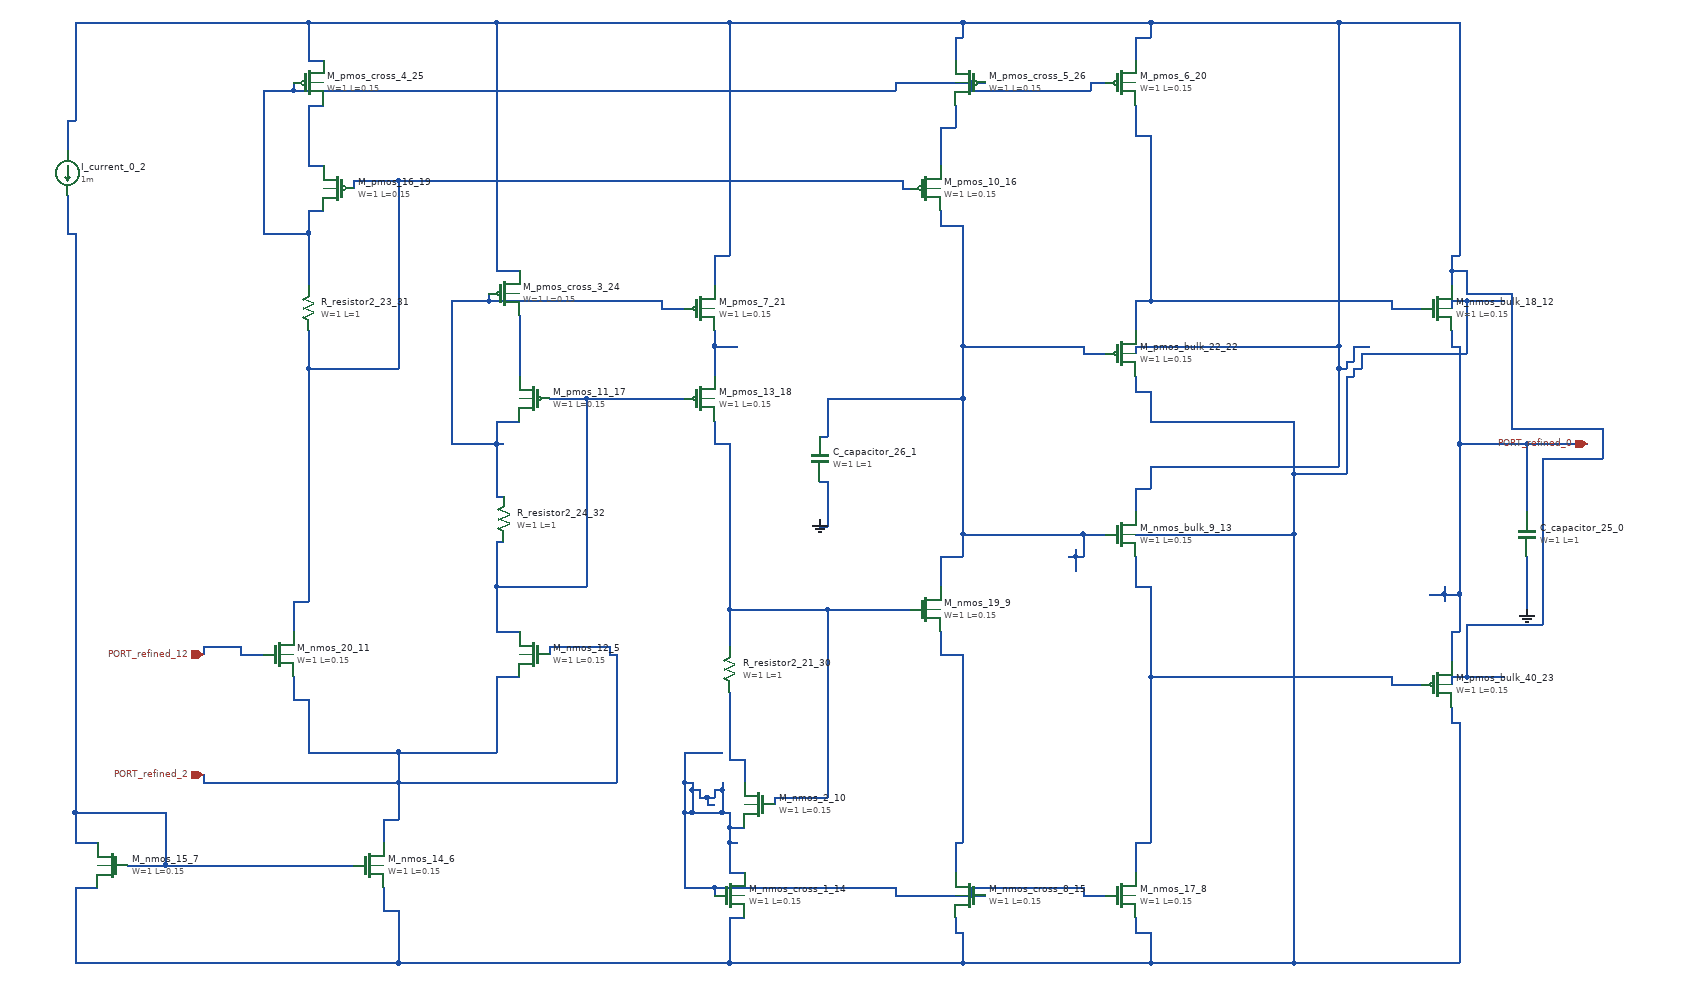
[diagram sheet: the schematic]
v {xschem version=3.4.8 file_version=1.2}
G {}
K {}
V {}
S {}
E {}
C {sky130_fd_pr/cap_mim_m3_1.sym} 2040 780 2 0 {name="C_capacitor_25_0" model=cap_mim_m3_1 W=1 L=1 MF=1 spiceprefix=X}
C {sky130_fd_pr/cap_mim_m3_1.sym} 1100 680 2 0 {name="C_capacitor_26_1" model=cap_mim_m3_1 W=1 L=1 MF=1 spiceprefix=X}
C {devices/isource.sym} 100 300 0 0 {name="I_current_0_2" value=1m}
C {devices/gnd.sym} 1100 760 0 0 {name="l_gnd_27_3" lab="GND"}
C {devices/gnd.sym} 2040 880 0 0 {name="l_gnd_28_4" lab="GND"}
C {sky130_fd_pr/nfet3_01v8.sym} 720 940 0 1 {name="M_nmos_12_5"
W=1
L=0.15
body=GND
nf=1
mult=1
ad="expr('int((@nf + 1)/2) * @W / @nf * 0.29')"
pd="expr('2*int((@nf + 1)/2) * (@W / @nf + 0.29)')"
as="expr('int((@nf + 2)/2) * @W / @nf * 0.29')"
ps="expr('2*int((@nf + 2)/2) * (@W / @nf + 0.29)')"
nrd="expr('0.29 / @W ')" nrs="expr('0.29 / @W ')"
sa=0 sb=0 sd=0
model=nfet_01v8
spiceprefix=X
}
C {sky130_fd_pr/nfet3_01v8.sym} 500 1220 0 0 {name="M_nmos_14_6"
W=1
L=0.15
body=GND
nf=1
mult=1
ad="expr('int((@nf + 1)/2) * @W / @nf * 0.29')"
pd="expr('2*int((@nf + 1)/2) * (@W / @nf + 0.29)')"
as="expr('int((@nf + 2)/2) * @W / @nf * 0.29')"
ps="expr('2*int((@nf + 2)/2) * (@W / @nf + 0.29)')"
nrd="expr('0.29 / @W ')" nrs="expr('0.29 / @W ')"
sa=0 sb=0 sd=0
model=nfet_01v8
spiceprefix=X
}
C {sky130_fd_pr/nfet3_01v8.sym} 160 1220 0 1 {name="M_nmos_15_7"
W=1
L=0.15
body=GND
nf=1
mult=1
ad="expr('int((@nf + 1)/2) * @W / @nf * 0.29')"
pd="expr('2*int((@nf + 1)/2) * (@W / @nf + 0.29)')"
as="expr('int((@nf + 2)/2) * @W / @nf * 0.29')"
ps="expr('2*int((@nf + 2)/2) * (@W / @nf + 0.29)')"
nrd="expr('0.29 / @W ')" nrs="expr('0.29 / @W ')"
sa=0 sb=0 sd=0
model=nfet_01v8
spiceprefix=X
}
C {sky130_fd_pr/nfet3_01v8.sym} 1500 1260 0 0 {name="M_nmos_17_8"
W=1
L=0.15
body=GND
nf=1
mult=1
ad="expr('int((@nf + 1)/2) * @W / @nf * 0.29')"
pd="expr('2*int((@nf + 1)/2) * (@W / @nf + 0.29)')"
as="expr('int((@nf + 2)/2) * @W / @nf * 0.29')"
ps="expr('2*int((@nf + 2)/2) * (@W / @nf + 0.29)')"
nrd="expr('0.29 / @W ')" nrs="expr('0.29 / @W ')"
sa=0 sb=0 sd=0
model=nfet_01v8
spiceprefix=X
}
C {sky130_fd_pr/nfet3_01v8.sym} 1240 880 0 0 {name="M_nmos_19_9"
W=1
L=0.15
body=GND
nf=1
mult=1
ad="expr('int((@nf + 1)/2) * @W / @nf * 0.29')"
pd="expr('2*int((@nf + 1)/2) * (@W / @nf + 0.29)')"
as="expr('int((@nf + 2)/2) * @W / @nf * 0.29')"
ps="expr('2*int((@nf + 2)/2) * (@W / @nf + 0.29)')"
nrd="expr('0.29 / @W ')" nrs="expr('0.29 / @W ')"
sa=0 sb=0 sd=0
model=nfet_01v8
spiceprefix=X
}
C {sky130_fd_pr/nfet3_01v8.sym} 1020 1140 0 1 {name="M_nmos_2_10"
W=1
L=0.15
body=GND
nf=1
mult=1
ad="expr('int((@nf + 1)/2) * @W / @nf * 0.29')"
pd="expr('2*int((@nf + 1)/2) * (@W / @nf + 0.29)')"
as="expr('int((@nf + 2)/2) * @W / @nf * 0.29')"
ps="expr('2*int((@nf + 2)/2) * (@W / @nf + 0.29)')"
nrd="expr('0.29 / @W ')" nrs="expr('0.29 / @W ')"
sa=0 sb=0 sd=0
model=nfet_01v8
spiceprefix=X
}
C {sky130_fd_pr/nfet3_01v8.sym} 380 940 0 0 {name="M_nmos_20_11"
W=1
L=0.15
body=GND
nf=1
mult=1
ad="expr('int((@nf + 1)/2) * @W / @nf * 0.29')"
pd="expr('2*int((@nf + 1)/2) * (@W / @nf + 0.29)')"
as="expr('int((@nf + 2)/2) * @W / @nf * 0.29')"
ps="expr('2*int((@nf + 2)/2) * (@W / @nf + 0.29)')"
nrd="expr('0.29 / @W ')" nrs="expr('0.29 / @W ')"
sa=0 sb=0 sd=0
model=nfet_01v8
spiceprefix=X
}
C {sky130_fd_pr/nfet_01v8.sym} 1920 480 0 0 {name="M_nmos_bulk_18_12"
W=1
L=0.15
nf=1 
mult=1
ad="expr('int((@nf + 1)/2) * @W / @nf * 0.29')"
pd="expr('2*int((@nf + 1)/2) * (@W / @nf + 0.29)')"
as="expr('int((@nf + 2)/2) * @W / @nf * 0.29')"
ps="expr('2*int((@nf + 2)/2) * (@W / @nf + 0.29)')"
nrd="expr('0.29 / @W ')" nrs="expr('0.29 / @W ')"
sa=0 sb=0 sd=0
model=nfet_01v8
spiceprefix=X
}
C {sky130_fd_pr/nfet_01v8.sym} 1500 780 0 0 {name="M_nmos_bulk_9_13"
W=1
L=0.15
nf=1 
mult=1
ad="expr('int((@nf + 1)/2) * @W / @nf * 0.29')"
pd="expr('2*int((@nf + 1)/2) * (@W / @nf + 0.29)')"
as="expr('int((@nf + 2)/2) * @W / @nf * 0.29')"
ps="expr('2*int((@nf + 2)/2) * (@W / @nf + 0.29)')"
nrd="expr('0.29 / @W ')" nrs="expr('0.29 / @W ')"
sa=0 sb=0 sd=0
model=nfet_01v8
spiceprefix=X
}
C {sky130_fd_pr/nfet3_01v8.sym} 980 1260 0 0 {name="M_nmos_cross_1_14"
W=1
L=0.15
body=GND
nf=1
mult=1
ad="expr('int((@nf + 1)/2) * @W / @nf * 0.29')"
pd="expr('2*int((@nf + 1)/2) * (@W / @nf + 0.29)')"
as="expr('int((@nf + 2)/2) * @W / @nf * 0.29')"
ps="expr('2*int((@nf + 2)/2) * (@W / @nf + 0.29)')"
nrd="expr('0.29 / @W ')" nrs="expr('0.29 / @W ')"
sa=0 sb=0 sd=0
model=nfet_01v8
spiceprefix=X
}
C {sky130_fd_pr/nfet3_01v8.sym} 1300 1260 0 1 {name="M_nmos_cross_8_15"
W=1
L=0.15
body=GND
nf=1
mult=1
ad="expr('int((@nf + 1)/2) * @W / @nf * 0.29')"
pd="expr('2*int((@nf + 1)/2) * (@W / @nf + 0.29)')"
as="expr('int((@nf + 2)/2) * @W / @nf * 0.29')"
ps="expr('2*int((@nf + 2)/2) * (@W / @nf + 0.29)')"
nrd="expr('0.29 / @W ')" nrs="expr('0.29 / @W ')"
sa=0 sb=0 sd=0
model=nfet_01v8
spiceprefix=X
}
C {sky130_fd_pr/pfet3_01v8.sym} 1240 320 0 0 {name="M_pmos_10_16"
W=1
L=0.15
body=VDD
nf=1
mult=1
ad="expr('int((@nf + 1)/2) * @W / @nf * 0.29')"
pd="expr('2*int((@nf + 1)/2) * (@W / @nf + 0.29)')"
as="expr('int((@nf + 2)/2) * @W / @nf * 0.29')"
ps="expr('2*int((@nf + 2)/2) * (@W / @nf + 0.29)')"
nrd="expr('0.29 / @W ')" nrs="expr('0.29 / @W ')"
sa=0 sb=0 sd=0
model=pfet_01v8
spiceprefix=X
}
C {sky130_fd_pr/pfet3_01v8.sym} 720 600 0 1 {name="M_pmos_11_17"
W=1
L=0.15
body=VDD
nf=1
mult=1
ad="expr('int((@nf + 1)/2) * @W / @nf * 0.29')"
pd="expr('2*int((@nf + 1)/2) * (@W / @nf + 0.29)')"
as="expr('int((@nf + 2)/2) * @W / @nf * 0.29')"
ps="expr('2*int((@nf + 2)/2) * (@W / @nf + 0.29)')"
nrd="expr('0.29 / @W ')" nrs="expr('0.29 / @W ')"
sa=0 sb=0 sd=0
model=pfet_01v8
spiceprefix=X
}
C {sky130_fd_pr/pfet3_01v8.sym} 940 600 0 0 {name="M_pmos_13_18"
W=1
L=0.15
body=VDD
nf=1
mult=1
ad="expr('int((@nf + 1)/2) * @W / @nf * 0.29')"
pd="expr('2*int((@nf + 1)/2) * (@W / @nf + 0.29)')"
as="expr('int((@nf + 2)/2) * @W / @nf * 0.29')"
ps="expr('2*int((@nf + 2)/2) * (@W / @nf + 0.29)')"
nrd="expr('0.29 / @W ')" nrs="expr('0.29 / @W ')"
sa=0 sb=0 sd=0
model=pfet_01v8
spiceprefix=X
}
C {sky130_fd_pr/pfet3_01v8.sym} 460 320 0 1 {name="M_pmos_16_19"
W=1
L=0.15
body=VDD
nf=1
mult=1
ad="expr('int((@nf + 1)/2) * @W / @nf * 0.29')"
pd="expr('2*int((@nf + 1)/2) * (@W / @nf + 0.29)')"
as="expr('int((@nf + 2)/2) * @W / @nf * 0.29')"
ps="expr('2*int((@nf + 2)/2) * (@W / @nf + 0.29)')"
nrd="expr('0.29 / @W ')" nrs="expr('0.29 / @W ')"
sa=0 sb=0 sd=0
model=pfet_01v8
spiceprefix=X
}
C {sky130_fd_pr/pfet3_01v8.sym} 1500 180 0 0 {name="M_pmos_6_20"
W=1
L=0.15
body=VDD
nf=1
mult=1
ad="expr('int((@nf + 1)/2) * @W / @nf * 0.29')"
pd="expr('2*int((@nf + 1)/2) * (@W / @nf + 0.29)')"
as="expr('int((@nf + 2)/2) * @W / @nf * 0.29')"
ps="expr('2*int((@nf + 2)/2) * (@W / @nf + 0.29)')"
nrd="expr('0.29 / @W ')" nrs="expr('0.29 / @W ')"
sa=0 sb=0 sd=0
model=pfet_01v8
spiceprefix=X
}
C {sky130_fd_pr/pfet3_01v8.sym} 940 480 0 0 {name="M_pmos_7_21"
W=1
L=0.15
body=VDD
nf=1
mult=1
ad="expr('int((@nf + 1)/2) * @W / @nf * 0.29')"
pd="expr('2*int((@nf + 1)/2) * (@W / @nf + 0.29)')"
as="expr('int((@nf + 2)/2) * @W / @nf * 0.29')"
ps="expr('2*int((@nf + 2)/2) * (@W / @nf + 0.29)')"
nrd="expr('0.29 / @W ')" nrs="expr('0.29 / @W ')"
sa=0 sb=0 sd=0
model=pfet_01v8
spiceprefix=X
}
C {sky130_fd_pr/pfet_01v8.sym} 1500 540 0 0 {name="M_pmos_bulk_22_22"
W=1
L=0.15
nf=1
mult=1
ad="expr('int((@nf + 1)/2) * @W / @nf * 0.29')"
pd="expr('2*int((@nf + 1)/2) * (@W / @nf + 0.29)')"
as="expr('int((@nf + 2)/2) * @W / @nf * 0.29')"
ps="expr('2*int((@nf + 2)/2) * (@W / @nf + 0.29)')"
nrd="expr('0.29 / @W ')" nrs="expr('0.29 / @W ')"
sa=0 sb=0 sd=0
model=pfet_01v8
spiceprefix=X
}
C {sky130_fd_pr/pfet_01v8.sym} 1920 980 0 0 {name="M_pmos_bulk_40_23"
W=1
L=0.15
nf=1
mult=1
ad="expr('int((@nf + 1)/2) * @W / @nf * 0.29')"
pd="expr('2*int((@nf + 1)/2) * (@W / @nf + 0.29)')"
as="expr('int((@nf + 2)/2) * @W / @nf * 0.29')"
ps="expr('2*int((@nf + 2)/2) * (@W / @nf + 0.29)')"
nrd="expr('0.29 / @W ')" nrs="expr('0.29 / @W ')"
sa=0 sb=0 sd=0
model=pfet_01v8
spiceprefix=X
}
C {sky130_fd_pr/pfet3_01v8.sym} 680 460 0 0 {name="M_pmos_cross_3_24"
W=1
L=0.15
body=VDD
nf=1
mult=1
ad="expr('int((@nf + 1)/2) * @W / @nf * 0.29')"
pd="expr('2*int((@nf + 1)/2) * (@W / @nf + 0.29)')"
as="expr('int((@nf + 2)/2) * @W / @nf * 0.29')"
ps="expr('2*int((@nf + 2)/2) * (@W / @nf + 0.29)')"
nrd="expr('0.29 / @W ')" nrs="expr('0.29 / @W ')"
sa=0 sb=0 sd=0
model=pfet_01v8
spiceprefix=X
}
C {sky130_fd_pr/pfet3_01v8.sym} 420 180 0 0 {name="M_pmos_cross_4_25"
W=1
L=0.15
body=VDD
nf=1
mult=1
ad="expr('int((@nf + 1)/2) * @W / @nf * 0.29')"
pd="expr('2*int((@nf + 1)/2) * (@W / @nf + 0.29)')"
as="expr('int((@nf + 2)/2) * @W / @nf * 0.29')"
ps="expr('2*int((@nf + 2)/2) * (@W / @nf + 0.29)')"
nrd="expr('0.29 / @W ')" nrs="expr('0.29 / @W ')"
sa=0 sb=0 sd=0
model=pfet_01v8
spiceprefix=X
}
C {sky130_fd_pr/pfet3_01v8.sym} 1300 180 0 1 {name="M_pmos_cross_5_26"
W=1
L=0.15
body=VDD
nf=1
mult=1
ad="expr('int((@nf + 1)/2) * @W / @nf * 0.29')"
pd="expr('2*int((@nf + 1)/2) * (@W / @nf + 0.29)')"
as="expr('int((@nf + 2)/2) * @W / @nf * 0.29')"
ps="expr('2*int((@nf + 2)/2) * (@W / @nf + 0.29)')"
nrd="expr('0.29 / @W ')" nrs="expr('0.29 / @W ')"
sa=0 sb=0 sd=0
model=pfet_01v8
spiceprefix=X
}
C {devices/ipin.sym} 2120 660 0 0 {name="p_port_29_27" lab="PORT_refined_0"}
C {devices/ipin.sym} 280 940 0 0 {name="p_port_30_28" lab="PORT_refined_12"}
C {devices/ipin.sym} 280 1100 0 0 {name="p_port_35_29" lab="PORT_refined_2"}
C {sky130_fd_pr/res_generic_po.sym} 980 960 2 0 {name="R_resistor2_21_30"
W=1
L=1
model=res_generic_po
spiceprefix=X
mult=1}
C {sky130_fd_pr/res_generic_po.sym} 420 480 2 0 {name="R_resistor2_23_31"
W=1
L=1
model=res_generic_po
spiceprefix=X
mult=1}
C {sky130_fd_pr/res_generic_po.sym} 680 760 2 0 {name="R_resistor2_24_32"
W=1
L=1
model=res_generic_po
spiceprefix=X
mult=1}
N 1940 910 1950 910 {}
N 1910 860 1930 860 {}
N 1930 860 1950 860 {}
N 1950 660 2040 660 {}
N 2040 660 2120 660 {}
N 1940 530 1950 530 {}
N 1930 870 1930 860 {}
N 1930 860 1930 850 {}
N 1940 950 1940 910 {}
N 1940 530 1940 510 {}
N 1950 910 1950 860 {}
N 1950 860 1950 660 {}
N 1950 660 1950 530 {}
N 2040 750 2040 660 {}
N 1100 770 1110 770 {}
N 1100 710 1110 710 {}
N 1100 770 1100 760 {}
N 1110 770 1110 710 {}
N 2040 880 2040 810 {}
N 980 1080 1000 1080 {}
N 980 1080 980 990 {}
N 1000 1110 1000 1080 {}
N 400 870 420 870 {}
N 420 560 540 560 {}
N 1210 320 1220 320 {}
N 480 310 540 310 {}
N 540 310 1210 310 {}
N 400 910 400 870 {}
N 420 870 420 560 {}
N 420 560 420 510 {}
N 480 320 480 310 {}
N 540 560 540 310 {}
N 1210 320 1210 310 {}
N 330 940 360 940 {}
N 280 930 330 930 {}
N 280 940 280 930 {}
N 330 940 330 930 {}
N 1940 970 1960 970 {}
N 1960 970 2010 970 {}
N 1960 900 2060 900 {}
N 1520 720 1540 720 {}
N 1540 690 1790 690 {}
N 2060 680 2140 680 {}
N 2020 640 2140 640 {}
N 1790 560 1800 560 {}
N 1800 550 1810 550 {}
N 1520 530 1790 530 {}
N 1810 530 1830 530 {}
N 1960 460 2020 460 {}
N 670 430 700 430 {}
N 1940 430 1960 430 {}
N 960 410 980 410 {}
N 1940 410 1950 410 {}
N 100 230 110 230 {}
N 420 150 440 150 {}
N 1280 120 1290 120 {}
N 1520 120 1540 120 {}
N 110 100 420 100 {}
N 420 100 670 100 {}
N 670 100 980 100 {}
N 980 100 1290 100 {}
N 1290 100 1540 100 {}
N 1540 100 1790 100 {}
N 1790 100 1950 100 {}
N 100 270 100 230 {}
N 110 230 110 100 {}
N 420 150 420 100 {}
N 670 430 670 100 {}
N 960 450 960 410 {}
N 980 410 980 100 {}
N 1280 150 1280 120 {}
N 1290 120 1290 100 {}
N 1520 750 1520 720 {}
N 1520 540 1520 530 {}
N 1520 150 1520 120 {}
N 1540 720 1540 690 {}
N 1540 120 1540 100 {}
N 1790 690 1790 560 {}
N 1790 560 1790 530 {}
N 1790 530 1790 100 {}
N 1800 560 1800 550 {}
N 1810 550 1810 530 {}
N 1940 980 1940 970 {}
N 1940 450 1940 430 {}
N 1940 430 1940 410 {}
N 1950 410 1950 100 {}
N 1960 970 1960 900 {}
N 1960 460 1960 430 {}
N 2020 640 2020 460 {}
N 2060 900 2060 680 {}
N 2140 680 2140 640 {}
N 1860 480 1900 480 {}
N 1520 470 1540 470 {}
N 1540 470 1860 470 {}
N 1520 250 1540 250 {}
N 1520 510 1520 470 {}
N 1520 250 1520 210 {}
N 1540 470 1540 250 {}
N 1860 480 1860 470 {}
N 1260 240 1280 240 {}
N 1260 290 1260 240 {}
N 1280 240 1280 210 {}
N 670 730 680 730 {}
N 610 660 670 660 {}
N 670 660 680 660 {}
N 670 630 700 630 {}
N 890 480 920 480 {}
N 610 470 660 470 {}
N 660 470 890 470 {}
N 610 660 610 470 {}
N 660 470 660 460 {}
N 670 730 670 660 {}
N 670 660 670 630 {}
N 890 480 890 470 {}
N 700 570 700 490 {}
N 670 910 700 910 {}
N 670 850 790 850 {}
N 670 790 680 790 {}
N 740 600 790 600 {}
N 790 600 920 600 {}
N 670 910 670 850 {}
N 670 850 670 790 {}
N 790 850 790 600 {}
N 960 530 990 530 {}
N 960 570 960 530 {}
N 960 530 960 510 {}
N 520 1160 540 1160 {}
N 280 1110 540 1110 {}
N 540 1110 830 1110 {}
N 420 1070 540 1070 {}
N 540 1070 670 1070 {}
N 400 1000 420 1000 {}
N 670 970 700 970 {}
N 820 940 830 940 {}
N 740 930 820 930 {}
N 280 1110 280 1100 {}
N 400 1000 400 970 {}
N 420 1070 420 1000 {}
N 520 1190 520 1160 {}
N 540 1160 540 1110 {}
N 540 1110 540 1070 {}
N 670 1070 670 970 {}
N 740 940 740 930 {}
N 820 940 820 930 {}
N 830 1110 830 940 {}
N 360 380 420 380 {}
N 420 350 440 350 {}
N 360 190 400 190 {}
N 400 190 1200 190 {}
N 1300 190 1460 190 {}
N 1200 180 1300 180 {}
N 1300 180 1320 180 {}
N 1460 180 1480 180 {}
N 360 380 360 190 {}
N 400 190 400 180 {}
N 420 450 420 380 {}
N 420 380 420 350 {}
N 1200 190 1200 180 {}
N 1300 190 1300 180 {}
N 1460 190 1460 180 {}
N 420 290 440 290 {}
N 420 210 440 210 {}
N 420 290 420 210 {}
N 110 1350 540 1350 {}
N 540 1350 980 1350 {}
N 980 1350 1290 1350 {}
N 1290 1350 1540 1350 {}
N 1540 1350 1730 1350 {}
N 1730 1350 1950 1350 {}
N 1280 1310 1290 1310 {}
N 1520 1310 1540 1310 {}
N 980 1290 1000 1290 {}
N 520 1280 540 1280 {}
N 110 1250 140 1250 {}
N 1940 1030 1950 1030 {}
N 1520 780 1730 780 {}
N 1730 700 1800 700 {}
N 1540 630 1730 630 {}
N 1520 590 1540 590 {}
N 1800 570 1810 570 {}
N 1810 560 1820 560 {}
N 1820 540 1960 540 {}
N 1940 470 1960 470 {}
N 1960 470 2010 470 {}
N 110 1350 110 1250 {}
N 520 1280 520 1250 {}
N 540 1350 540 1280 {}
N 980 1350 980 1290 {}
N 1280 1310 1280 1290 {}
N 1290 1350 1290 1310 {}
N 1520 1310 1520 1290 {}
N 1520 590 1520 570 {}
N 1540 1350 1540 1310 {}
N 1540 630 1540 590 {}
N 1730 1350 1730 780 {}
N 1730 780 1730 700 {}
N 1730 700 1730 630 {}
N 1800 700 1800 570 {}
N 1810 570 1810 560 {}
N 1820 560 1820 540 {}
N 1940 1030 1940 1010 {}
N 1940 480 1940 470 {}
N 1950 1350 1950 1030 {}
N 1960 540 1960 470 {}
N 180 1220 230 1220 {}
N 230 1220 480 1220 {}
N 110 1190 140 1190 {}
N 110 1150 230 1150 {}
N 100 380 110 380 {}
N 100 380 100 330 {}
N 110 1190 110 1150 {}
N 110 1150 110 380 {}
N 230 1220 230 1150 {}
N 1520 1190 1540 1190 {}
N 1860 980 1900 980 {}
N 1540 970 1860 970 {}
N 1520 850 1540 850 {}
N 1520 1230 1520 1190 {}
N 1520 850 1520 810 {}
N 1540 1190 1540 970 {}
N 1540 970 1540 850 {}
N 1860 980 1860 970 {}
N 1200 1260 1300 1260 {}
N 1300 1260 1320 1260 {}
N 1450 1260 1480 1260 {}
N 920 1250 960 1250 {}
N 960 1250 1200 1250 {}
N 1300 1250 1450 1250 {}
N 980 1230 1000 1230 {}
N 980 1190 990 1190 {}
N 980 1170 1000 1170 {}
N 920 1150 930 1150 {}
N 930 1150 970 1150 {}
N 970 1150 980 1150 {}
N 950 1140 960 1140 {}
N 940 1130 950 1130 {}
N 950 1130 960 1130 {}
N 930 1120 940 1120 {}
N 960 1120 970 1120 {}
N 920 1110 930 1110 {}
N 920 1070 970 1070 {}
N 920 1250 920 1150 {}
N 920 1150 920 1110 {}
N 920 1110 920 1070 {}
N 930 1150 930 1120 {}
N 930 1120 930 1110 {}
N 940 1130 940 1120 {}
N 950 1140 950 1130 {}
N 960 1260 960 1250 {}
N 960 1130 960 1120 {}
N 970 1150 970 1120 {}
N 970 1120 970 1110 {}
N 980 1230 980 1190 {}
N 980 1190 980 1170 {}
N 980 1170 980 1150 {}
N 1200 1260 1200 1250 {}
N 1300 1260 1300 1250 {}
N 1450 1260 1450 1250 {}
N 1260 810 1290 810 {}
N 1430 810 1440 810 {}
N 1440 810 1450 810 {}
N 1290 780 1450 780 {}
N 1450 780 1480 780 {}
N 1100 650 1110 650 {}
N 1110 600 1290 600 {}
N 1450 540 1480 540 {}
N 1290 530 1450 530 {}
N 1260 370 1290 370 {}
N 1110 650 1110 600 {}
N 1260 850 1260 810 {}
N 1260 370 1260 350 {}
N 1290 810 1290 780 {}
N 1290 780 1290 600 {}
N 1290 600 1290 530 {}
N 1290 530 1290 370 {}
N 1440 830 1440 810 {}
N 1440 810 1440 800 {}
N 1450 810 1450 780 {}
N 1450 540 1450 530 {}
N 1280 1190 1290 1190 {}
N 1260 940 1290 940 {}
N 1260 940 1260 910 {}
N 1280 1230 1280 1190 {}
N 1290 1190 1290 940 {}
N 1040 1130 1110 1130 {}
N 980 880 1110 880 {}
N 1110 880 1220 880 {}
N 960 660 980 660 {}
N 960 660 960 630 {}
N 980 930 980 880 {}
N 980 880 980 660 {}
N 1040 1140 1040 1130 {}
N 1110 1130 1110 880 {}
